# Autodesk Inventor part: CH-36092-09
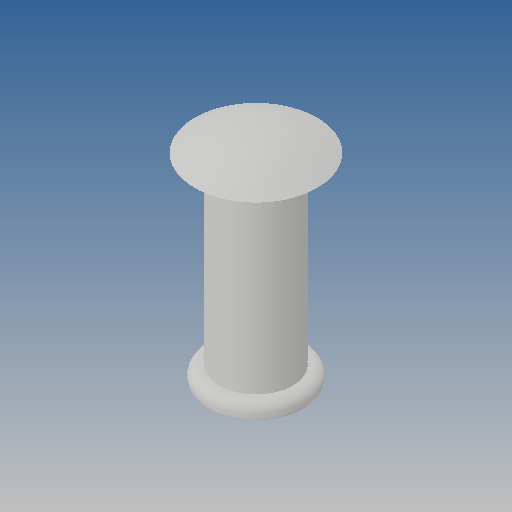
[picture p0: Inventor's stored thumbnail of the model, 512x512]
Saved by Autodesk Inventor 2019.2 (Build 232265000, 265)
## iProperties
Created: 2012-09
Part Number: CH-36092-09
Material: Ogólny
Document SubType Name: Modeling
Designer: CADENGINEERING4
Density: 1 g/cm^3
Appearance: Domyślna
Author: CADENGINEERING4
Revision Number: ÈÎºÎ
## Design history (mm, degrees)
feature "Ô²½Ç2"
node "Bryła1"
